VERSION 5.8 ;
BUSBITCHARS "[]" ;
DIVIDERCHAR "/" ;
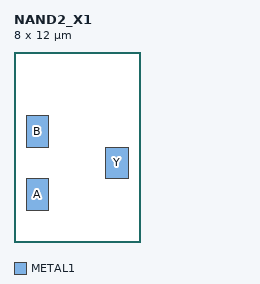
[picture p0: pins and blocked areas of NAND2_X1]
MACRO NAND2_X1
  CLASS CORE ;
  SIZE 8.0 BY 12.0 ;
  PIN A
    DIRECTION INPUT ;
    PORT
      LAYER METAL1 ;
      RECT 0.8 2.0 2.2 4.0 ;
    END
  END A
  PIN B
    DIRECTION INPUT ;
    PORT
      LAYER METAL1 ;
      RECT 0.8 6.0 2.2 8.0 ;
    END
  END B
  PIN Y
    DIRECTION OUTPUT ;
    PORT
      LAYER METAL1 ;
      RECT 5.8 4.0 7.2 6.0 ;
    END
  END Y
END NAND2_X1
END LIBRARY
